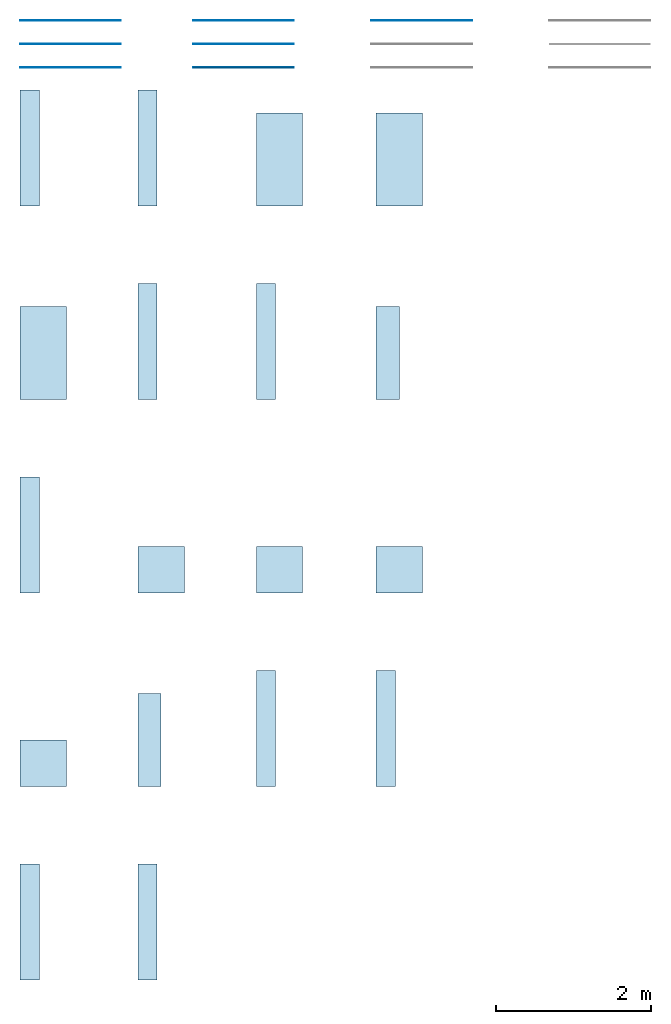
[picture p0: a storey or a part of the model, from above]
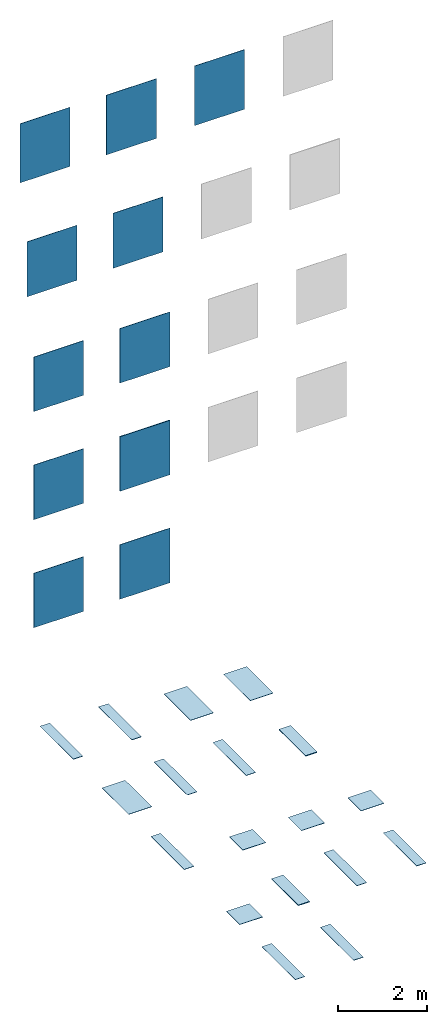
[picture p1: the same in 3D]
Properties of the parts of a building model (IFC2X3)

# File
Description: ViewDefinition [CoordinationView_V2.0], RevitIdentifiers [VersionGUID: e541cde4-21f0-433d-9453-daf3c8eb5631, NumberOfSaves: 230], CoordinateReference [CoordinateBase: Shared Coordinates, ProjectSite: Internal]
File name: Project Number
Time: 2024-11-25T10:44:30+01:00
Written by: ODA SDAI 24.3
Made in: Autodesk Revit 24.1.11.26 (ENU) - IFC 24.1.11.26

# IfcProject, Project Number
LongName: Refin-Blended; Phase: Project Status

# IfcSite, Default
RefLatitude: 51, 30, 0, 549316; RefLongitude: 0, -7, -34, -450321; RefElevation: 0 mm

# IfcBuilding
Pset_BuildingCommon - NumberOfStoreys: 1

# IfcBuildingStorey: Level:Circle Head - Project Datum (2)
Pset_AirSideSystemInformation - sets with these values: 2
Name | LongName = Name | Elevation (mm)
Level 0 | Level 0 | 0
Level 1 | Level 1 | 4000

# IfcSlab: Floor:Floor_Tiles_Refin-Eik-Almond-25x150 RJ96, Floor:Floor_Tiles_Refin-Eik-Almond-25x150 RJ96:304668
In: Level 0
Type - PredefinedType: FLOOR; Material: Eik-Almond-25x150 RJ96 9 mm, <Unnamed> 1 mm
Type - Pset_ConcreteElementGeneral - FireRating: INERT
Type - Pset_ElementShading - Color: BEIGE
Type - Pset_FireRatingProperties - SurfaceSpreadOfFlame: INERT
Type - Pset_ManufacturerOccurrence - BarCode: N/A; SerialNumber: N/A
Type - Pset_ManufacturerTypeInformation - ArticleNumber: RJ96; ModelReference: RJ96; ModelLabel: ALMOND R 25X150; Manufacturer: info@refin.it; ProductionYear: N/A
Type - Pset_PrecastConcreteElementGeneral - SerialNumber: N/A
Type - Pset_ProductRequirements - Name: Eik_Almond_25X150 R; Category: Pr_35_93_96_19:Ceramic tiles
Type - Pset_QuantityTakeOff - Reference: N/A
Type - Pset_ReinforcementBarPitchOfSlab - Description: PORCELAIN STONEWARE TILE; Reference: N/A
Type - Pset_SlabCommon - Reference: N/A; IsExternal: no; AcousticRating: N/A; FireRating: INERT; SurfaceSpreadOfFlame: INERT
Type - Pset_Warranty - WarrantyContent: N/A; Exclusions: N/A
Pset_QuantityTakeOff - sets with these values: 2
Pset_SlabCommon - LoadBearing: no; PitchAngle: 0 deg

# IfcSlab: Floor:Floor_Tiles_Refin-Eik-Ash-25x150 RJ97, Floor:Floor_Tiles_Refin-Eik-Ash-25x150 RJ97:324498
In: Level 0
Type - PredefinedType: FLOOR; Material: Eik-Ash-25x150 RJ97 9 mm, <Unnamed> 1 mm
Type - Pset_ConcreteElementGeneral - FireRating: INERT
Type - Pset_ElementShading - Color: LIGHT GREY
Type - Pset_FireRatingProperties - SurfaceSpreadOfFlame: INERT
Type - Pset_ManufacturerOccurrence - BarCode: N/A; SerialNumber: N/A
Type - Pset_ManufacturerTypeInformation - ArticleNumber: RJ97; ModelReference: RJ97; ModelLabel: ASH R 25X150; Manufacturer: info@refin.it; ProductionYear: N/A
Type - Pset_PrecastConcreteElementGeneral - SerialNumber: N/A
Type - Pset_ProductRequirements - Name: Eik_Ash_25X150 R; Category: Pr_35_93_96_19:Ceramic tiles
Type - Pset_QuantityTakeOff - Reference: N/A
Type - Pset_ReinforcementBarPitchOfSlab - Description: PORCELAIN STONEWARE TILE; Reference: N/A
Type - Pset_SlabCommon - Reference: N/A; IsExternal: no; AcousticRating: N/A; FireRating: INERT; SurfaceSpreadOfFlame: INERT
Type - Pset_Warranty - WarrantyContent: N/A; Exclusions: N/A
Pset_QuantityTakeOff - sets with these values: 2
Pset_SlabCommon - LoadBearing: no; PitchAngle: 0 deg

# IfcSlab: Floor:Floor_Tiles_Refin-Eik-Cannè-Almond-60x120 RK81, Floor:Floor_Tiles_Refin-Eik-Cannè-Almond-60x120 RK81:340715
In: Level 0
Type - PredefinedType: FLOOR; Material: Eik-Canné-Almond-60x120 RK81 9 mm, <Unnamed> 1 mm
Type - Pset_ConcreteElementGeneral - FireRating: INERT
Type - Pset_ElementShading - Color: BEIGE
Type - Pset_FireRatingProperties - SurfaceSpreadOfFlame: INERT
Type - Pset_ManufacturerOccurrence - BarCode: N/A; SerialNumber: N/A
Type - Pset_ManufacturerTypeInformation - ArticleNumber: RK81; ModelReference: RK81; ModelLabel: CANNE' ALMOND R 60X120; Manufacturer: info@refin.it; ProductionYear: N/A
Type - Pset_PrecastConcreteElementGeneral - SerialNumber: N/A
Type - Pset_ProductRequirements - Name: Eik_Cannè_Almond_60X120 R; Category: Pr_35_93_96_19:Ceramic tiles
Type - Pset_QuantityTakeOff - Reference: N/A
Type - Pset_ReinforcementBarPitchOfSlab - Description: PORCELAIN STONEWARE TILE; Reference: N/A
Type - Pset_SlabCommon - Reference: N/A; IsExternal: no; AcousticRating: N/A; FireRating: INERT; SurfaceSpreadOfFlame: INERT
Type - Pset_Warranty - WarrantyContent: N/A; Exclusions: N/A
Pset_QuantityTakeOff - sets with these values: 2
Pset_SlabCommon - LoadBearing: no; PitchAngle: 0 deg

# IfcSlab: Floor:Floor_Tiles_Refin-Eik-Cannè-Honey-60x120 RK82, Floor:Floor_Tiles_Refin-Eik-Cannè-Honey-60x120 RK82:341038
In: Level 0
Type - PredefinedType: FLOOR; Material: Eik-Canné-Honey-60x120 RK82 9 mm, <Unnamed> 1 mm
Type - Pset_ConcreteElementGeneral - FireRating: INERT
Type - Pset_ElementShading - Color: LIGHT BROWN
Type - Pset_FireRatingProperties - SurfaceSpreadOfFlame: INERT
Type - Pset_ManufacturerOccurrence - BarCode: N/A; SerialNumber: N/A
Type - Pset_ManufacturerTypeInformation - ArticleNumber: RK81; ModelReference: RK81; ModelLabel: CANNE' HONEY R 60X120; Manufacturer: info@refin.it; ProductionYear: N/A
Type - Pset_PrecastConcreteElementGeneral - SerialNumber: N/A
Type - Pset_ProductRequirements - Name: Eik_Cannè_Honey_60X120 R; Category: Pr_35_93_96_19:Ceramic tiles
Type - Pset_QuantityTakeOff - Reference: N/A
Type - Pset_ReinforcementBarPitchOfSlab - Description: PORCELAIN STONEWARE TILE; Reference: N/A
Type - Pset_SlabCommon - Reference: N/A; IsExternal: no; AcousticRating: N/A; FireRating: INERT; SurfaceSpreadOfFlame: INERT
Type - Pset_Warranty - WarrantyContent: N/A; Exclusions: N/A
Pset_QuantityTakeOff - sets with these values: 2
Pset_SlabCommon - LoadBearing: no; PitchAngle: 0 deg

# IfcSlab: Floor:Floor_Tiles_Refin-Eik-Cannè-Natural-60x120 RK83, Floor:Floor_Tiles_Refin-Eik-Cannè-Natural-60x120 RK83:341279
In: Level 0
Type - PredefinedType: FLOOR; Material: Eik-Canné-Natural-60x120 RK83 9 mm, <Unnamed> 1 mm
Type - Pset_ConcreteElementGeneral - FireRating: INERT
Type - Pset_ElementShading - Color: LIGHT BROWN
Type - Pset_FireRatingProperties - SurfaceSpreadOfFlame: INERT
Type - Pset_ManufacturerOccurrence - BarCode: N/A; SerialNumber: N/A
Type - Pset_ManufacturerTypeInformation - ArticleNumber: RK83; ModelReference: RK83; ModelLabel: CANNE' NATURAL R 60X120; Manufacturer: info@refin.it; ProductionYear: N/A
Type - Pset_PrecastConcreteElementGeneral - SerialNumber: N/A
Type - Pset_ProductRequirements - Name: Eik_Cannè_Natural_60X120 R; Category: Pr_35_93_96_19:Ceramic tiles
Type - Pset_QuantityTakeOff - Reference: N/A
Type - Pset_ReinforcementBarPitchOfSlab - Description: PORCELAIN STONEWARE TILE; Reference: N/A
Type - Pset_SlabCommon - Reference: N/A; IsExternal: no; AcousticRating: N/A; FireRating: INERT; SurfaceSpreadOfFlame: INERT
Type - Pset_Warranty - WarrantyContent: N/A; Exclusions: N/A
Pset_QuantityTakeOff - sets with these values: 2
Pset_SlabCommon - LoadBearing: no; PitchAngle: 0 deg

# IfcSlab: Floor:Floor_Tiles_Refin-Eik-Choco-25x150 RJ98, Floor:Floor_Tiles_Refin-Eik-Choco-25x150 RJ98:341467
In: Level 0
Type - PredefinedType: FLOOR; Material: Eik-Choco-25x150 RJ98 9 mm, <Unnamed> 1 mm
Type - Pset_ConcreteElementGeneral - FireRating: INERT
Type - Pset_ElementShading - Color: BROWN
Type - Pset_FireRatingProperties - SurfaceSpreadOfFlame: INERT
Type - Pset_ManufacturerOccurrence - BarCode: N/A; SerialNumber: N/A
Type - Pset_ManufacturerTypeInformation - ArticleNumber: RJ98; ModelReference: RJ98; ModelLabel: CHOCO R 25X150; Manufacturer: info@refin.it; ProductionYear: N/A
Type - Pset_PrecastConcreteElementGeneral - SerialNumber: N/A
Type - Pset_ProductRequirements - Name: Eik_Choco_25X150 R; Category: Pr_35_93_96_19:Ceramic tiles
Type - Pset_QuantityTakeOff - Reference: N/A
Type - Pset_ReinforcementBarPitchOfSlab - Description: PORCELAIN STONEWARE TILE; Reference: N/A
Type - Pset_SlabCommon - Reference: N/A; IsExternal: no; AcousticRating: N/A; FireRating: INERT; SurfaceSpreadOfFlame: INERT
Type - Pset_Warranty - WarrantyContent: N/A; Exclusions: N/A
Pset_QuantityTakeOff - sets with these values: 2
Pset_SlabCommon - LoadBearing: no; PitchAngle: 0 deg

# IfcSlab: Floor:Floor_Tiles_Refin-Eik-Coffee-25x150 RJ99, Floor:Floor_Tiles_Refin-Eik-Coffee-25x150 RJ99:341755
In: Level 0
Type - PredefinedType: FLOOR; Material: Eik-Coffee-25x150 RJ99 9 mm, <Unnamed> 1 mm
Type - Pset_ConcreteElementGeneral - FireRating: INERT
Type - Pset_ElementShading - Color: DARK BROWN
Type - Pset_FireRatingProperties - SurfaceSpreadOfFlame: INERT
Type - Pset_ManufacturerOccurrence - BarCode: N/A; SerialNumber: N/A
Type - Pset_ManufacturerTypeInformation - ArticleNumber: RJ99; ModelReference: RJ99; ModelLabel: COFFEE R 25X150; Manufacturer: info@refin.it; ProductionYear: N/A
Type - Pset_PrecastConcreteElementGeneral - SerialNumber: N/A
Type - Pset_ProductRequirements - Name: Eik_Coffee_25X150 R; Category: Pr_35_93_96_19:Ceramic tiles
Type - Pset_QuantityTakeOff - Reference: N/A
Type - Pset_ReinforcementBarPitchOfSlab - Description: PORCELAIN STONEWARE TILE; Reference: N/A
Type - Pset_SlabCommon - Reference: N/A; IsExternal: no; AcousticRating: N/A; FireRating: INERT; SurfaceSpreadOfFlame: INERT
Type - Pset_Warranty - WarrantyContent: N/A; Exclusions: N/A
Pset_QuantityTakeOff - sets with these values: 2
Pset_SlabCommon - LoadBearing: no; PitchAngle: 0 deg

# IfcSlab: Floor:Floor_Tiles_Refin-Eik-Honey-25x150 RK00, Floor:Floor_Tiles_Refin-Eik-Honey-25x150 RK00:342299
In: Level 0
Type - PredefinedType: FLOOR; Material: Eik-Honey-25x150 RK00 9 mm, <Unnamed> 1 mm
Type - Pset_ConcreteElementGeneral - FireRating: INERT
Type - Pset_ElementShading - Color: LIGHT BROWN
Type - Pset_FireRatingProperties - SurfaceSpreadOfFlame: INERT
Type - Pset_ManufacturerOccurrence - BarCode: N/A; SerialNumber: N/A
Type - Pset_ManufacturerTypeInformation - ArticleNumber: RK00; ModelReference: RK00; ModelLabel: HONEY R 25X150; Manufacturer: info@refin.it; ProductionYear: N/A
Type - Pset_PrecastConcreteElementGeneral - SerialNumber: N/A
Type - Pset_ProductRequirements - Name: Eik_Honey_25X150 R; Category: Pr_35_93_96_19:Ceramic tiles
Type - Pset_QuantityTakeOff - Reference: N/A
Type - Pset_ReinforcementBarPitchOfSlab - Description: PORCELAIN STONEWARE TILE; Reference: N/A
Type - Pset_SlabCommon - Reference: N/A; IsExternal: no; AcousticRating: N/A; FireRating: INERT; SurfaceSpreadOfFlame: INERT
Type - Pset_Warranty - WarrantyContent: N/A; Exclusions: N/A
Pset_QuantityTakeOff - sets with these values: 2
Pset_SlabCommon - LoadBearing: no; PitchAngle: 0 deg

# IfcSlab: Floor:Floor_Tiles_Refin-Eik-Honey-OUT2.0-30x120 RN20, Floor:Floor_Tiles_Refin-Eik-Honey-OUT2.0-30x120 RN20:341933
In: Level 0
Type - PredefinedType: FLOOR; Material: Eik-Honey-OUT2.0-30x120 RN20 20 mm, <Unnamed> 1 mm
Type - Pset_ConcreteElementGeneral - FireRating: INERT
Type - Pset_ElementShading - Color: LIGHT BROWN
Type - Pset_FireRatingProperties - SurfaceSpreadOfFlame: INERT
Type - Pset_ManufacturerOccurrence - BarCode: N/A; SerialNumber: N/A
Type - Pset_ManufacturerTypeInformation - ArticleNumber: RN20; ModelReference: RN20; ModelLabel: HONEY OUT2.0 R 30X120; Manufacturer: info@refin.it; ProductionYear: N/A
Type - Pset_PrecastConcreteElementGeneral - SerialNumber: N/A
Type - Pset_ProductRequirements - Name: Eik_Honey_OUT2.0_30X120 R; Category: Pr_35_93_96_19:Ceramic tiles
Type - Pset_QuantityTakeOff - Reference: N/A
Type - Pset_ReinforcementBarPitchOfSlab - Description: PORCELAIN STONEWARE TILE; Reference: N/A
Type - Pset_SlabCommon - Reference: N/A; IsExternal: no; AcousticRating: N/A; FireRating: INERT; SurfaceSpreadOfFlame: INERT
Type - Pset_Warranty - WarrantyContent: N/A; Exclusions: N/A
Pset_QuantityTakeOff - sets with these values: 2
Pset_SlabCommon - LoadBearing: no; PitchAngle: 0 deg

# IfcSlab: Floor:Floor_Tiles_Refin-Eik-Leaf-Almond-60x60 RL61, Floor:Floor_Tiles_Refin-Eik-Leaf-Almond-60x60 RL61:342545
In: Level 0
Type - PredefinedType: FLOOR; Material: Eik-Leaf-Almond-60x60 RL61 9 mm, <Unnamed> 1 mm
Type - Pset_ConcreteElementGeneral - FireRating: INERT
Type - Pset_ElementShading - Color: BEIGE
Type - Pset_FireRatingProperties - SurfaceSpreadOfFlame: INERT
Type - Pset_ManufacturerOccurrence - BarCode: N/A; SerialNumber: N/A
Type - Pset_ManufacturerTypeInformation - ArticleNumber: RL61; ModelReference: RL61; ModelLabel: LEAF ALMOND R 60X60; Manufacturer: info@refin.it; ProductionYear: N/A
Type - Pset_PrecastConcreteElementGeneral - SerialNumber: N/A
Type - Pset_ProductRequirements - Name: Eik_Leaf_Almond_60X60 R; Category: Pr_35_93_96_19:Ceramic tiles
Type - Pset_QuantityTakeOff - Reference: N/A
Type - Pset_ReinforcementBarPitchOfSlab - Description: PORCELAIN STONEWARE TILE; Reference: N/A
Type - Pset_SlabCommon - Reference: N/A; IsExternal: no; AcousticRating: N/A; FireRating: INERT; SurfaceSpreadOfFlame: INERT
Type - Pset_Warranty - WarrantyContent: N/A; Exclusions: N/A
Pset_QuantityTakeOff - sets with these values: 2
Pset_SlabCommon - LoadBearing: no; PitchAngle: 0 deg

# IfcSlab: Floor:Floor_Tiles_Refin-Eik-Leaf-Honey-60x60 RL62, Floor:Floor_Tiles_Refin-Eik-Leaf-Honey-60x60 RL62:342787
In: Level 0
Type - PredefinedType: FLOOR; Material: Eik-Leaf-Honey-60x60 RL62 9 mm, <Unnamed> 1 mm
Type - Pset_ConcreteElementGeneral - FireRating: INERT
Type - Pset_ElementShading - Color: LIGHT BROWN
Type - Pset_FireRatingProperties - SurfaceSpreadOfFlame: INERT
Type - Pset_ManufacturerOccurrence - BarCode: N/A; SerialNumber: N/A
Type - Pset_ManufacturerTypeInformation - ArticleNumber: RL62; ModelReference: RL62; ModelLabel: LEAF HONEY R 60X60; Manufacturer: info@refin.it; ProductionYear: N/A
Type - Pset_PrecastConcreteElementGeneral - SerialNumber: N/A
Type - Pset_ProductRequirements - Name: Eik_Leaf_Honey_60X60 R; Category: Pr_35_93_96_19:Ceramic tiles
Type - Pset_QuantityTakeOff - Reference: N/A
Type - Pset_ReinforcementBarPitchOfSlab - Description: PORCELAIN STONEWARE TILE; Reference: N/A
Type - Pset_SlabCommon - Reference: N/A; IsExternal: no; AcousticRating: N/A; FireRating: INERT; SurfaceSpreadOfFlame: INERT
Type - Pset_Warranty - WarrantyContent: N/A; Exclusions: N/A
Pset_QuantityTakeOff - sets with these values: 2
Pset_SlabCommon - LoadBearing: no; PitchAngle: 0 deg

# IfcSlab: Floor:Floor_Tiles_Refin-Eik-Leaf-Natural-60x60 RL63, Floor:Floor_Tiles_Refin-Eik-Leaf-Natural-60x60 RL63:342912
In: Level 0
Type - PredefinedType: FLOOR; Material: Eik-Leaf-Natural-60x60 RL63 9 mm, <Unnamed> 1 mm
Type - Pset_ConcreteElementGeneral - FireRating: INERT
Type - Pset_ElementShading - Color: LIGHT BROWN
Type - Pset_FireRatingProperties - SurfaceSpreadOfFlame: INERT
Type - Pset_ManufacturerOccurrence - BarCode: N/A; SerialNumber: N/A
Type - Pset_ManufacturerTypeInformation - ArticleNumber: RL63; ModelReference: RL63; ModelLabel: LEAF NATURAL R 60X60; Manufacturer: info@refin.it; ProductionYear: N/A
Type - Pset_PrecastConcreteElementGeneral - SerialNumber: N/A
Type - Pset_ProductRequirements - Name: Eik_Leaf_Natural_60X60 R; Category: Pr_35_93_96_19:Ceramic tiles
Type - Pset_QuantityTakeOff - Reference: N/A
Type - Pset_ReinforcementBarPitchOfSlab - Description: PORCELAIN STONEWARE TILE; Reference: N/A
Type - Pset_SlabCommon - Reference: N/A; IsExternal: no; AcousticRating: N/A; FireRating: INERT; SurfaceSpreadOfFlame: INERT
Type - Pset_Warranty - WarrantyContent: N/A; Exclusions: N/A
Pset_QuantityTakeOff - sets with these values: 2
Pset_SlabCommon - LoadBearing: no; PitchAngle: 0 deg

# IfcSlab: Floor:Floor_Tiles_Refin-Eik-Leaf-Nut-60x60 RL64, Floor:Floor_Tiles_Refin-Eik-Leaf-Nut-60x60 RL64:343152
In: Level 0
Type - PredefinedType: FLOOR; Material: Eik-Leaf-Nut-60x60 RL64 9 mm, <Unnamed> 1 mm
Type - Pset_ConcreteElementGeneral - FireRating: INERT
Type - Pset_ElementShading - Color: BROWN
Type - Pset_FireRatingProperties - SurfaceSpreadOfFlame: INERT
Type - Pset_ManufacturerOccurrence - BarCode: N/A; SerialNumber: N/A
Type - Pset_ManufacturerTypeInformation - ArticleNumber: RL64; ModelReference: RL64; ModelLabel: LEAF NUT R 60X60; Manufacturer: info@refin.it; ProductionYear: N/A
Type - Pset_PrecastConcreteElementGeneral - SerialNumber: N/A
Type - Pset_ProductRequirements - Name: Eik_Leaf_Nut_60X60 R; Category: Pr_35_93_96_19:Ceramic tiles
Type - Pset_QuantityTakeOff - Reference: N/A
Type - Pset_ReinforcementBarPitchOfSlab - Description: PORCELAIN STONEWARE TILE; Reference: N/A
Type - Pset_SlabCommon - Reference: N/A; IsExternal: no; AcousticRating: N/A; FireRating: INERT; SurfaceSpreadOfFlame: INERT
Type - Pset_Warranty - WarrantyContent: N/A; Exclusions: N/A
Pset_QuantityTakeOff - sets with these values: 2
Pset_SlabCommon - LoadBearing: no; PitchAngle: 0 deg

# IfcSlab: Floor:Floor_Tiles_Refin-Eik-Natural-25x150 RK01, Floor:Floor_Tiles_Refin-Eik-Natural-25x150 RK01:343709
In: Level 0
Type - PredefinedType: FLOOR; Material: Eik-Natural-25x150 RK01 9 mm, <Unnamed> 1 mm
Type - Pset_ConcreteElementGeneral - FireRating: INERT
Type - Pset_ElementShading - Color: LIGHT BROWN
Type - Pset_FireRatingProperties - SurfaceSpreadOfFlame: INERT
Type - Pset_ManufacturerOccurrence - BarCode: N/A; SerialNumber: N/A
Type - Pset_ManufacturerTypeInformation - ArticleNumber: RK01; ModelReference: RK01; ModelLabel: NATURAL R 25X150; Manufacturer: info@refin.it; ProductionYear: N/A
Type - Pset_PrecastConcreteElementGeneral - SerialNumber: N/A
Type - Pset_ProductRequirements - Name: Eik_Natural_25X150 R; Category: Pr_35_93_96_19:Ceramic tiles
Type - Pset_QuantityTakeOff - Reference: N/A
Type - Pset_ReinforcementBarPitchOfSlab - Description: PORCELAIN STONEWARE TILE; Reference: N/A
Type - Pset_SlabCommon - Reference: N/A; IsExternal: no; AcousticRating: N/A; FireRating: INERT; SurfaceSpreadOfFlame: INERT
Type - Pset_Warranty - WarrantyContent: N/A; Exclusions: N/A
Pset_QuantityTakeOff - sets with these values: 2
Pset_SlabCommon - LoadBearing: no; PitchAngle: 0 deg

# IfcSlab: Floor:Floor_Tiles_Refin-Eik-Natural-OUT2.0-30x120 RN21, Floor:Floor_Tiles_Refin-Eik-Natural-OUT2.0-30x120 RN21:343508
In: Level 0
Type - PredefinedType: FLOOR; Material: Eik-Natural-OUT2.0-30x120 RN21 20 mm, <Unnamed> 1 mm
Type - Pset_ConcreteElementGeneral - FireRating: INERT
Type - Pset_ElementShading - Color: LIGHT BROWN
Type - Pset_FireRatingProperties - SurfaceSpreadOfFlame: INERT
Type - Pset_ManufacturerOccurrence - BarCode: N/A; SerialNumber: N/A
Type - Pset_ManufacturerTypeInformation - ArticleNumber: RN21; ModelReference: RN21; ModelLabel: NATURAL OUT2.0 R 30X120; Manufacturer: info@refin.it; ProductionYear: N/A
Type - Pset_PrecastConcreteElementGeneral - SerialNumber: N/A
Type - Pset_ProductRequirements - Name: Eik_Natural_OUT2.0_30X120 R; Category: Pr_35_93_96_19:Ceramic tiles
Type - Pset_QuantityTakeOff - Reference: N/A
Type - Pset_ReinforcementBarPitchOfSlab - Description: PORCELAIN STONEWARE TILE; Reference: N/A
Type - Pset_SlabCommon - Reference: N/A; IsExternal: no; AcousticRating: N/A; FireRating: INERT; SurfaceSpreadOfFlame: INERT
Type - Pset_Warranty - WarrantyContent: N/A; Exclusions: N/A
Pset_QuantityTakeOff - sets with these values: 2
Pset_SlabCommon - LoadBearing: no; PitchAngle: 0 deg

# IfcSlab: Floor:Floor_Tiles_Refin-Eik-Nut-25x150 RK02, Floor:Floor_Tiles_Refin-Eik-Nut-25x150 RK02:343986
In: Level 0
Type - PredefinedType: FLOOR; Material: Eik-Nut-25x150 RK02 9 mm, <Unnamed> 1 mm
Type - Pset_ConcreteElementGeneral - FireRating: INERT
Type - Pset_ElementShading - Color: BROWN
Type - Pset_FireRatingProperties - SurfaceSpreadOfFlame: INERT
Type - Pset_ManufacturerOccurrence - BarCode: N/A; SerialNumber: N/A
Type - Pset_ManufacturerTypeInformation - ArticleNumber: RK02; ModelReference: RK02; ModelLabel: NUT R 25X150; Manufacturer: info@refin.it; ProductionYear: N/A
Type - Pset_PrecastConcreteElementGeneral - SerialNumber: N/A
Type - Pset_ProductRequirements - Name: Eik_Nut_25X150 R; Category: Pr_35_93_96_19:Ceramic tiles
Type - Pset_QuantityTakeOff - Reference: N/A
Type - Pset_ReinforcementBarPitchOfSlab - Description: PORCELAIN STONEWARE TILE; Reference: N/A
Type - Pset_SlabCommon - Reference: N/A; IsExternal: no; AcousticRating: N/A; FireRating: INERT; SurfaceSpreadOfFlame: INERT
Type - Pset_Warranty - WarrantyContent: N/A; Exclusions: N/A
Pset_QuantityTakeOff - sets with these values: 2
Pset_SlabCommon - LoadBearing: no; PitchAngle: 0 deg

# IfcSlab: Floor:Floor_Tiles_Refin-Eik-Rice-25x150 RK03, Floor:Floor_Tiles_Refin-Eik-Rice-25x150 RK03:344762
In: Level 0
Type - PredefinedType: FLOOR; Material: Eik-Rice-25x150 RK03 9 mm, <Unnamed> 1 mm
Type - Pset_ConcreteElementGeneral - FireRating: INERT
Type - Pset_ElementShading - Color: WHITE
Type - Pset_FireRatingProperties - SurfaceSpreadOfFlame: INERT
Type - Pset_ManufacturerOccurrence - BarCode: N/A; SerialNumber: N/A
Type - Pset_ManufacturerTypeInformation - ArticleNumber: RK03; ModelReference: RK03; ModelLabel: RICE R 25X150; Manufacturer: info@refin.it; ProductionYear: N/A
Type - Pset_PrecastConcreteElementGeneral - SerialNumber: N/A
Type - Pset_ProductRequirements - Name: Eik_Rice_25X150 R; Category: Pr_35_93_96_19:Ceramic tiles
Type - Pset_QuantityTakeOff - Reference: N/A
Type - Pset_ReinforcementBarPitchOfSlab - Description: PORCELAIN STONEWARE TILE; Reference: N/A
Type - Pset_SlabCommon - Reference: N/A; IsExternal: no; AcousticRating: N/A; FireRating: INERT; SurfaceSpreadOfFlame: INERT
Type - Pset_Warranty - WarrantyContent: N/A; Exclusions: N/A
Pset_QuantityTakeOff - sets with these values: 2
Pset_SlabCommon - LoadBearing: no; PitchAngle: 0 deg

# IfcSlab: Floor:Floor_Tiles_Refin-Eik-Sand-25x150 RK04, Floor:Floor_Tiles_Refin-Eik-Sand-25x150 RK04:345082
In: Level 0
Type - PredefinedType: FLOOR; Material: Eik-Sand-25x150 RK04 9 mm, <Unnamed> 1 mm
Type - Pset_ConcreteElementGeneral - FireRating: INERT
Type - Pset_ElementShading - Color: BEIGE
Type - Pset_FireRatingProperties - SurfaceSpreadOfFlame: INERT
Type - Pset_ManufacturerOccurrence - BarCode: N/A; SerialNumber: N/A
Type - Pset_ManufacturerTypeInformation - ArticleNumber: RK04; ModelReference: RK04; ModelLabel: SAND R 25X150; Manufacturer: info@refin.it; ProductionYear: N/A
Type - Pset_PrecastConcreteElementGeneral - SerialNumber: N/A
Type - Pset_ProductRequirements - Name: Eik_Sand_25X150 R; Category: Pr_35_93_96_19:Ceramic tiles
Type - Pset_QuantityTakeOff - Reference: N/A
Type - Pset_ReinforcementBarPitchOfSlab - Description: PORCELAIN STONEWARE TILE; Reference: N/A
Type - Pset_SlabCommon - Reference: N/A; IsExternal: no; AcousticRating: N/A; FireRating: INERT; SurfaceSpreadOfFlame: INERT
Type - Pset_Warranty - WarrantyContent: N/A; Exclusions: N/A
Pset_QuantityTakeOff - sets with these values: 2
Pset_SlabCommon - LoadBearing: no; PitchAngle: 0 deg

# IfcWallStandardCase: Basic Wall:Wall_Tiles_Refin-Eik-Almond-25x150 RJ96, Basic Wall:Wall_Tiles_Refin-Eik-Almond-25x150 RJ96:334895
In: Level 0
Type - PredefinedType: STANDARD; Material: <Unnamed> 1 mm, Eik-Almond-25x150 RJ96 9 mm
Type - Pset_ElementShading - Color: BEIGE
Type - Pset_FireRatingProperties - SurfaceSpreadOfFlame: INERT
Type - Pset_ManufacturerOccurrence - BarCode: N/A; SerialNumber: N/A
Type - Pset_ManufacturerTypeInformation - ArticleNumber: RJ96; ModelReference: RJ96; ModelLabel: ALMOND R 25X150; Manufacturer: info@refin.it; ProductionYear: N/A
Type - Pset_PrecastConcreteElementGeneral - SerialNumber: N/A
Type - Pset_ProductRequirements - Name: Eik_Almond_25X150 R; Category: Pr_35_93_96_19:Ceramic tiles
Type - Pset_QuantityTakeOff - Reference: N/A
Type - Pset_ReinforcementBarPitchOfWall - Description: PORCELAIN STONEWARE TILE; Reference: N/A
Type - Pset_WallCommon - Reference: N/A; IsExternal: no; AcousticRating: N/A; SurfaceSpreadOfFlame: INERT
Type - Pset_Warranty - WarrantyContent: N/A; Exclusions: N/A
Pset_QuantityTakeOff - sets with these values: 2
Pset_WallCommon - LoadBearing: no; ExtendToStructure: no

# IfcWallStandardCase: Basic Wall:Wall_Tiles_Refin-Eik-Ash-25x150 RJ97, Basic Wall:Wall_Tiles_Refin-Eik-Ash-25x150 RJ97:333696
In: Level 0
Type - PredefinedType: STANDARD; Material: <Unnamed> 1 mm, Eik-Almond-25x150 RJ96 9 mm
Type - Pset_ElementShading - Color: LIGHT GREY
Type - Pset_FireRatingProperties - SurfaceSpreadOfFlame: INERT
Type - Pset_ManufacturerOccurrence - BarCode: N/A; SerialNumber: N/A
Type - Pset_ManufacturerTypeInformation - ArticleNumber: RJ97; ModelReference: RJ97; ModelLabel: ALMOND R 25X150; Manufacturer: info@refin.it; ProductionYear: N/A
Type - Pset_PrecastConcreteElementGeneral - SerialNumber: N/A
Type - Pset_ProductRequirements - Name: Eik_Ash_25X150 R; Category: Pr_35_93_96_19:Ceramic tiles
Type - Pset_QuantityTakeOff - Reference: N/A
Type - Pset_ReinforcementBarPitchOfWall - Description: PORCELAIN STONEWARE TILE; Reference: N/A
Type - Pset_WallCommon - Reference: N/A; IsExternal: no; AcousticRating: N/A; SurfaceSpreadOfFlame: INERT
Type - Pset_Warranty - WarrantyContent: N/A; Exclusions: N/A
Pset_QuantityTakeOff - sets with these values: 2
Pset_WallCommon - LoadBearing: no; ExtendToStructure: no

# IfcWallStandardCase: Basic Wall:Wall_Tiles_Refin-Eik-Canné-Almond-60x120 RK81, Basic Wall:Wall_Tiles_Refin-Eik-Canné-Almond-60x120 RK81:334553
In: Level 0
Type - PredefinedType: STANDARD; Material: <Unnamed> 1 mm, Eik-Canné-Almond-60x120 RK81 9 mm
Type - Pset_ElementShading - Color: BEIGE
Type - Pset_FireRatingProperties - SurfaceSpreadOfFlame: INERT
Type - Pset_ManufacturerOccurrence - BarCode: N/A; SerialNumber: N/A
Type - Pset_ManufacturerTypeInformation - ArticleNumber: RK81; ModelReference: RK81; ModelLabel: CANNE' ALMOND R 60X120; Manufacturer: info@refin.it; ProductionYear: N/A
Type - Pset_PrecastConcreteElementGeneral - SerialNumber: N/A
Type - Pset_ProductRequirements - Name: Eik_Canné_Almond_60X120 R; Category: Pr_35_93_96_19:Ceramic tiles
Type - Pset_QuantityTakeOff - Reference: N/A
Type - Pset_ReinforcementBarPitchOfWall - Description: PORCELAIN STONEWARE TILE; Reference: N/A
Type - Pset_WallCommon - Reference: N/A; IsExternal: no; AcousticRating: N/A; SurfaceSpreadOfFlame: INERT
Type - Pset_Warranty - WarrantyContent: N/A; Exclusions: N/A
Pset_QuantityTakeOff - sets with these values: 2
Pset_WallCommon - LoadBearing: no; ExtendToStructure: no

# IfcWallStandardCase: Basic Wall:Wall_Tiles_Refin-Eik-Canné-Honey-60x120 RK82, Basic Wall:Wall_Tiles_Refin-Eik-Canné-Honey-60x120 RK82:341158
In: Level 0
Type - PredefinedType: STANDARD; Material: <Unnamed> 1 mm, Eik-Canné-Honey-60x120 RK82 9 mm
Type - Pset_ElementShading - Color: LIGHT BROWN
Type - Pset_FireRatingProperties - SurfaceSpreadOfFlame: INERT
Type - Pset_ManufacturerOccurrence - BarCode: N/A; SerialNumber: N/A
Type - Pset_ManufacturerTypeInformation - ArticleNumber: RK82; ModelReference: RK82; ModelLabel: CANNE' HONEY R 60X120; Manufacturer: info@refin.it; ProductionYear: N/A
Type - Pset_PrecastConcreteElementGeneral - SerialNumber: N/A
Type - Pset_ProductRequirements - Name: Eik_Canné_Honey_60X120 R; Category: Pr_35_93_96_19:Ceramic tiles
Type - Pset_QuantityTakeOff - Reference: N/A
Type - Pset_ReinforcementBarPitchOfWall - Description: PORCELAIN STONEWARE TILE; Reference: N/A
Type - Pset_WallCommon - Reference: N/A; IsExternal: no; AcousticRating: N/A; SurfaceSpreadOfFlame: INERT
Type - Pset_Warranty - WarrantyContent: N/A; Exclusions: N/A
Pset_QuantityTakeOff - sets with these values: 2
Pset_WallCommon - LoadBearing: no; ExtendToStructure: no

# IfcWallStandardCase: Basic Wall:Wall_Tiles_Refin-Eik-Canné-Natural-60x120 RK83, Basic Wall:Wall_Tiles_Refin-Eik-Canné-Natural-60x120 RK83:335038
In: Level 0
Type - PredefinedType: STANDARD; Material: <Unnamed> 1 mm, Eik-Canné-Natural-60x120 RK83 9 mm
Type - Pset_ElementShading - Color: LIGHT BROWN
Type - Pset_FireRatingProperties - SurfaceSpreadOfFlame: INERT
Type - Pset_ManufacturerOccurrence - BarCode: N/A; SerialNumber: N/A
Type - Pset_ManufacturerTypeInformation - ArticleNumber: RK83; ModelReference: RK83; ModelLabel: CANNE' NATURAL R 60X120; Manufacturer: info@refin.it; ProductionYear: N/A
Type - Pset_PrecastConcreteElementGeneral - SerialNumber: N/A
Type - Pset_ProductRequirements - Name: Eik_Canné_Natural_60X120 R; Category: Pr_35_93_96_19:Ceramic tiles
Type - Pset_QuantityTakeOff - Reference: N/A
Type - Pset_ReinforcementBarPitchOfWall - Description: PORCELAIN STONEWARE TILE; Reference: N/A
Type - Pset_WallCommon - Reference: N/A; IsExternal: no; AcousticRating: N/A; SurfaceSpreadOfFlame: INERT
Type - Pset_Warranty - WarrantyContent: N/A; Exclusions: N/A
Pset_QuantityTakeOff - sets with these values: 2
Pset_WallCommon - LoadBearing: no; ExtendToStructure: no

# IfcWallStandardCase: Basic Wall:Wall_Tiles_Refin-Eik-Choco-25x150 RJ98, Basic Wall:Wall_Tiles_Refin-Eik-Choco-25x150 RJ98:335490
In: Level 0
Type - PredefinedType: STANDARD; Material: <Unnamed> 1 mm, Eik-Choco-25x150 RJ98 9 mm
Type - Pset_ElementShading - Color: BROWN
Type - Pset_FireRatingProperties - SurfaceSpreadOfFlame: INERT
Type - Pset_ManufacturerOccurrence - BarCode: N/A; SerialNumber: N/A
Type - Pset_ManufacturerTypeInformation - ArticleNumber: RJ98; ModelReference: RJ98; ModelLabel: CHOCO R 25X150; Manufacturer: info@refin.it; ProductionYear: N/A
Type - Pset_PrecastConcreteElementGeneral - SerialNumber: N/A
Type - Pset_ProductRequirements - Name: Eik_Choco_25X150 R; Category: Pr_35_93_96_19:Ceramic tiles
Type - Pset_QuantityTakeOff - Reference: N/A
Type - Pset_ReinforcementBarPitchOfWall - Description: PORCELAIN STONEWARE TILE; Reference: N/A
Type - Pset_WallCommon - Reference: N/A; IsExternal: no; AcousticRating: N/A; SurfaceSpreadOfFlame: INERT
Type - Pset_Warranty - WarrantyContent: N/A; Exclusions: N/A
Pset_QuantityTakeOff - sets with these values: 2
Pset_WallCommon - LoadBearing: no; ExtendToStructure: no

# IfcWallStandardCase: Basic Wall:Wall_Tiles_Refin-Eik-Coffee-25x150 RJ99, Basic Wall:Wall_Tiles_Refin-Eik-Coffee-25x150 RJ99:335882
In: Level 0
Type - PredefinedType: STANDARD; Material: <Unnamed> 1 mm, Eik-Coffee-25x150 RJ99 9 mm
Type - Pset_ElementShading - Color: DARK BROWN
Type - Pset_FireRatingProperties - SurfaceSpreadOfFlame: INERT
Type - Pset_ManufacturerOccurrence - BarCode: N/A; SerialNumber: N/A
Type - Pset_ManufacturerTypeInformation - ArticleNumber: RJ99; ModelReference: RJ99; ModelLabel: COFFEE R 25X150; Manufacturer: info@refin.it; ProductionYear: N/A
Type - Pset_PrecastConcreteElementGeneral - SerialNumber: N/A
Type - Pset_ProductRequirements - Name: Eik_Coffee_25X150 R; Category: Pr_35_93_96_19:Ceramic tiles
Type - Pset_QuantityTakeOff - Reference: N/A
Type - Pset_ReinforcementBarPitchOfWall - Description: PORCELAIN STONEWARE TILE; Reference: N/A
Type - Pset_WallCommon - Reference: N/A; IsExternal: no; AcousticRating: N/A; SurfaceSpreadOfFlame: INERT
Type - Pset_Warranty - WarrantyContent: N/A; Exclusions: N/A
Pset_QuantityTakeOff - sets with these values: 2
Pset_WallCommon - LoadBearing: no; ExtendToStructure: no

# IfcWallStandardCase: Basic Wall:Wall_Tiles_Refin-Eik-Honey-25x150 RK00, Basic Wall:Wall_Tiles_Refin-Eik-Honey-25x150 RK00:336183
In: Level 0
Type - PredefinedType: STANDARD; Material: <Unnamed> 1 mm, Eik-Honey-25x150 RK00 9 mm
Type - Pset_ElementShading - Color: LIGHT BROWN
Type - Pset_FireRatingProperties - SurfaceSpreadOfFlame: INERT
Type - Pset_ManufacturerOccurrence - BarCode: N/A; SerialNumber: N/A
Type - Pset_ManufacturerTypeInformation - ArticleNumber: RK00; ModelReference: RK00; ModelLabel: HONEY R 25X150; Manufacturer: info@refin.it; ProductionYear: N/A
Type - Pset_PrecastConcreteElementGeneral - SerialNumber: N/A
Type - Pset_ProductRequirements - Name: Eik_Honey_25X150 R; Category: Pr_35_93_96_19:Ceramic tiles
Type - Pset_QuantityTakeOff - Reference: N/A
Type - Pset_ReinforcementBarPitchOfWall - Description: PORCELAIN STONEWARE TILE; Reference: N/A
Type - Pset_WallCommon - Reference: N/A; IsExternal: no; AcousticRating: N/A; SurfaceSpreadOfFlame: INERT
Type - Pset_Warranty - WarrantyContent: N/A; Exclusions: N/A
Pset_QuantityTakeOff - sets with these values: 2
Pset_WallCommon - LoadBearing: no; ExtendToStructure: no

# IfcWallStandardCase: Basic Wall:Wall_Tiles_Refin-Eik-Honey-OUT2.0-30x120 RN20, Basic Wall:Wall_Tiles_Refin-Eik-Honey-OUT2.0-30x120 RN20:340784
In: Level 0
Type - PredefinedType: STANDARD; Material: <Unnamed> 1 mm, Eik-Honey-OUT2.0-30x120 RN20 20 mm
Type - Pset_ElementShading - Color: LIGHT BROWN
Type - Pset_FireRatingProperties - SurfaceSpreadOfFlame: INERT
Type - Pset_ManufacturerOccurrence - BarCode: N/A; SerialNumber: N/A
Type - Pset_ManufacturerTypeInformation - ArticleNumber: RN20; ModelReference: RN20; ModelLabel: HONEY OUT2.0 R 30X120; Manufacturer: info@refin.it; ProductionYear: N/A
Type - Pset_PrecastConcreteElementGeneral - SerialNumber: N/A
Type - Pset_ProductRequirements - Name: Eik_Honey_OUT2.0_30X120 R; Category: Pr_35_93_96_19:Ceramic tiles
Type - Pset_QuantityTakeOff - Reference: N/A
Type - Pset_ReinforcementBarPitchOfWall - Description: PORCELAIN STONEWARE TILE; Reference: N/A
Type - Pset_WallCommon - Reference: N/A; IsExternal: no; AcousticRating: N/A; SurfaceSpreadOfFlame: INERT
Type - Pset_Warranty - WarrantyContent: N/A; Exclusions: N/A
Pset_QuantityTakeOff - sets with these values: 2
Pset_WallCommon - LoadBearing: no; ExtendToStructure: no

# IfcWallStandardCase: Basic Wall:Wall_Tiles_Refin-Eik-Leaf-Almond-60x60 RL61, Basic Wall:Wall_Tiles_Refin-Eik-Leaf-Almond-60x60 RL61:342594
In: Level 0
Type - PredefinedType: STANDARD; Material: <Unnamed> 1 mm, Eik-Leaf-Almond-60x60 RL61 9 mm
Type - Pset_ElementShading - Color: BEIGE
Type - Pset_FireRatingProperties - SurfaceSpreadOfFlame: INERT
Type - Pset_ManufacturerOccurrence - BarCode: N/A; SerialNumber: N/A
Type - Pset_ManufacturerTypeInformation - ArticleNumber: RL61; ModelReference: RL61; ModelLabel: LEAF ALMOND R 60X60; Manufacturer: info@refin.it; ProductionYear: N/A
Type - Pset_PrecastConcreteElementGeneral - SerialNumber: N/A
Type - Pset_ProductRequirements - Name: Eik_Leaf_Almond_60X60 R; Category: Pr_35_93_96_19:Ceramic tiles
Type - Pset_QuantityTakeOff - Reference: N/A
Type - Pset_ReinforcementBarPitchOfWall - Description: PORCELAIN STONEWARE TILE; Reference: N/A
Type - Pset_WallCommon - Reference: N/A; IsExternal: no; AcousticRating: N/A; SurfaceSpreadOfFlame: INERT
Type - Pset_Warranty - WarrantyContent: N/A; Exclusions: N/A
Pset_QuantityTakeOff - sets with these values: 2
Pset_WallCommon - LoadBearing: no; ExtendToStructure: no

# IfcWallStandardCase: Basic Wall:Wall_Tiles_Refin-Eik-Leaf-Honey-60x60 RL62, Basic Wall:Wall_Tiles_Refin-Eik-Leaf-Honey-60x60 RL62:342842
In: Level 0
Type - PredefinedType: STANDARD; Material: <Unnamed> 1 mm, Eik-Leaf-Honey-60x60 RL62 9 mm
Type - Pset_ElementShading - Color: LIGHT BROWN
Type - Pset_FireRatingProperties - SurfaceSpreadOfFlame: INERT
Type - Pset_ManufacturerOccurrence - BarCode: N/A; SerialNumber: N/A
Type - Pset_ManufacturerTypeInformation - ArticleNumber: RL62; ModelReference: RL62; ModelLabel: LEAF HONEY R 60X60; Manufacturer: info@refin.it; ProductionYear: N/A
Type - Pset_PrecastConcreteElementGeneral - SerialNumber: N/A
Type - Pset_ProductRequirements - Name: Eik_Leaf_Honey_60X60 R; Category: Pr_35_93_96_19:Ceramic tiles
Type - Pset_QuantityTakeOff - Reference: N/A
Type - Pset_ReinforcementBarPitchOfWall - Description: PORCELAIN STONEWARE TILE; Reference: N/A
Type - Pset_WallCommon - Reference: N/A; IsExternal: no; AcousticRating: N/A; SurfaceSpreadOfFlame: INERT
Type - Pset_Warranty - WarrantyContent: N/A; Exclusions: N/A
Pset_QuantityTakeOff - sets with these values: 2
Pset_WallCommon - LoadBearing: no; ExtendToStructure: no

# IfcWallStandardCase: Basic Wall:Wall_Tiles_Refin-Eik-Leaf-Natural-60x60 RL63, Basic Wall:Wall_Tiles_Refin-Eik-Leaf-Natural-60x60 RL63:342942
In: Level 0
Type - PredefinedType: STANDARD; Material: <Unnamed> 1 mm, Eik-Leaf-Natural-60x60 RL63 9 mm
Type - Pset_ElementShading - Color: LIGHT BROWN
Type - Pset_FireRatingProperties - SurfaceSpreadOfFlame: INERT
Type - Pset_ManufacturerOccurrence - BarCode: N/A; SerialNumber: N/A
Type - Pset_ManufacturerTypeInformation - ArticleNumber: RL63; ModelReference: RL63; ModelLabel: LEAF NATURAL R 60X60; Manufacturer: info@refin.it; ProductionYear: N/A
Type - Pset_PrecastConcreteElementGeneral - SerialNumber: N/A
Type - Pset_ProductRequirements - Name: Eik_Leaf_Natural_60X60 R; Category: Pr_35_93_96_19:Ceramic tiles
Type - Pset_QuantityTakeOff - Reference: N/A
Type - Pset_ReinforcementBarPitchOfWall - Description: PORCELAIN STONEWARE TILE; Reference: N/A
Type - Pset_WallCommon - Reference: N/A; IsExternal: no; AcousticRating: N/A; SurfaceSpreadOfFlame: INERT
Type - Pset_Warranty - WarrantyContent: N/A; Exclusions: N/A
Pset_QuantityTakeOff - sets with these values: 2
Pset_WallCommon - LoadBearing: no; ExtendToStructure: no

# IfcWallStandardCase: Basic Wall:Wall_Tiles_Refin-Eik-Leaf-Nut-60x60 RL64, Basic Wall:Wall_Tiles_Refin-Eik-Leaf-Nut-60x60 RL64:343330
In: Level 0
Type - PredefinedType: STANDARD; Material: <Unnamed> 1 mm, Eik-Leaf-Nut-60x60 RL64 9 mm
Type - Pset_ElementShading - Color: BROWN
Type - Pset_FireRatingProperties - SurfaceSpreadOfFlame: INERT
Type - Pset_ManufacturerOccurrence - BarCode: N/A; SerialNumber: N/A
Type - Pset_ManufacturerTypeInformation - ArticleNumber: RL64; ModelReference: RL64; ModelLabel: LEAF NUT R 60X60; Manufacturer: info@refin.it; ProductionYear: N/A
Type - Pset_PrecastConcreteElementGeneral - SerialNumber: N/A
Type - Pset_ProductRequirements - Name: Eik_Leaf_Nut_60X60 R; Category: Pr_35_93_96_19:Ceramic tiles
Type - Pset_QuantityTakeOff - Reference: N/A
Type - Pset_ReinforcementBarPitchOfWall - Description: PORCELAIN STONEWARE TILE; Reference: N/A
Type - Pset_WallCommon - Reference: N/A; IsExternal: no; AcousticRating: N/A; SurfaceSpreadOfFlame: INERT
Type - Pset_Warranty - WarrantyContent: N/A; Exclusions: N/A
Pset_QuantityTakeOff - sets with these values: 2
Pset_WallCommon - LoadBearing: no; ExtendToStructure: no

# IfcWallStandardCase: Basic Wall:Wall_Tiles_Refin-Eik-Natural-25x150 RK01, Basic Wall:Wall_Tiles_Refin-Eik-Natural-25x150 RK01:343836
In: Level 0
Type - PredefinedType: STANDARD; Material: <Unnamed> 1 mm, Eik-Natural-25x150 RK01 9 mm
Type - Pset_ElementShading - Color: LIGHT BROWN
Type - Pset_FireRatingProperties - SurfaceSpreadOfFlame: INERT
Type - Pset_ManufacturerOccurrence - BarCode: N/A; SerialNumber: N/A
Type - Pset_ManufacturerTypeInformation - ArticleNumber: RK01; ModelReference: RK01; ModelLabel: NATURAL R 25X150; Manufacturer: info@refin.it; ProductionYear: N/A
Type - Pset_PrecastConcreteElementGeneral - SerialNumber: N/A
Type - Pset_ProductRequirements - Name: Eik_Natural_25X150 R; Category: Pr_35_93_96_19:Ceramic tiles
Type - Pset_QuantityTakeOff - Reference: N/A
Type - Pset_ReinforcementBarPitchOfWall - Description: PORCELAIN STONEWARE TILE; Reference: N/A
Type - Pset_WallCommon - Reference: N/A; IsExternal: no; AcousticRating: N/A; SurfaceSpreadOfFlame: INERT
Type - Pset_Warranty - WarrantyContent: N/A; Exclusions: N/A
Pset_QuantityTakeOff - sets with these values: 2
Pset_WallCommon - LoadBearing: no; ExtendToStructure: no

# IfcWallStandardCase: Basic Wall:Wall_Tiles_Refin-Eik-Natural-OUT2.0-30x120 RN21, Basic Wall:Wall_Tiles_Refin-Eik-Natural-OUT2.0-30x120 RN21:343548
In: Level 0
Type - PredefinedType: STANDARD; Material: <Unnamed> 1 mm, Eik-Natural-OUT2.0-30x120 RN21 20 mm
Type - Pset_ElementShading - Color: LIGHT BROWN
Type - Pset_FireRatingProperties - SurfaceSpreadOfFlame: INERT
Type - Pset_ManufacturerOccurrence - BarCode: N/A; SerialNumber: N/A
Type - Pset_ManufacturerTypeInformation - ArticleNumber: RN21; ModelReference: RN21; ModelLabel: NATURAL OUT2.0 R 30X120; Manufacturer: info@refin.it; ProductionYear: N/A
Type - Pset_PrecastConcreteElementGeneral - SerialNumber: N/A
Type - Pset_ProductRequirements - Name: Eik_Natural_OUT2.0_30X120 R; Category: Pr_35_93_96_19:Ceramic tiles
Type - Pset_QuantityTakeOff - Reference: N/A
Type - Pset_ReinforcementBarPitchOfWall - Description: PORCELAIN STONEWARE TILE; Reference: N/A
Type - Pset_WallCommon - Reference: N/A; IsExternal: no; AcousticRating: N/A; SurfaceSpreadOfFlame: INERT
Type - Pset_Warranty - WarrantyContent: N/A; Exclusions: N/A
Pset_QuantityTakeOff - sets with these values: 2
Pset_WallCommon - LoadBearing: no; ExtendToStructure: no

# IfcWallStandardCase: Basic Wall:Wall_Tiles_Refin-Eik-Nut-25x150 RK02, Basic Wall:Wall_Tiles_Refin-Eik-Nut-25x150 RK02:344019
In: Level 0
Type - PredefinedType: STANDARD; Material: <Unnamed> 1 mm, Eik-Nut-25x150 RK02 9 mm
Type - Pset_ElementShading - Color: BROWN
Type - Pset_FireRatingProperties - SurfaceSpreadOfFlame: INERT
Type - Pset_ManufacturerOccurrence - BarCode: N/A; SerialNumber: N/A
Type - Pset_ManufacturerTypeInformation - ArticleNumber: RK02; ModelReference: RK02; ModelLabel: NUT R 25X150; Manufacturer: info@refin.it; ProductionYear: N/A
Type - Pset_PrecastConcreteElementGeneral - SerialNumber: N/A
Type - Pset_ProductRequirements - Name: Eik_Nut_25X150 R; Category: Pr_35_93_96_19:Ceramic tiles
Type - Pset_QuantityTakeOff - Reference: N/A
Type - Pset_ReinforcementBarPitchOfWall - Description: PORCELAIN STONEWARE TILE; Reference: N/A
Type - Pset_WallCommon - Reference: N/A; IsExternal: no; AcousticRating: N/A; SurfaceSpreadOfFlame: INERT
Type - Pset_Warranty - WarrantyContent: N/A; Exclusions: N/A
Pset_QuantityTakeOff - sets with these values: 2
Pset_WallCommon - LoadBearing: no; ExtendToStructure: no

# IfcWallStandardCase: Basic Wall:Wall_Tiles_Refin-Eik-Rice-25x150 RK03, Basic Wall:Wall_Tiles_Refin-Eik-Rice-25x150 RK03:344949
In: Level 0
Type - PredefinedType: STANDARD; Material: <Unnamed> 1 mm, Eik-Rice-25x150 RK03 9 mm
Type - Pset_ElementShading - Color: WHITE
Type - Pset_FireRatingProperties - SurfaceSpreadOfFlame: INERT
Type - Pset_ManufacturerOccurrence - BarCode: N/A; SerialNumber: N/A
Type - Pset_ManufacturerTypeInformation - ArticleNumber: RK03; ModelReference: RK03; ModelLabel: RICE R 25X150; Manufacturer: info@refin.it; ProductionYear: N/A
Type - Pset_PrecastConcreteElementGeneral - SerialNumber: N/A
Type - Pset_ProductRequirements - Name: Eik_Rice_25X150 R; Category: Pr_35_93_96_19:Ceramic tiles
Type - Pset_QuantityTakeOff - Reference: N/A
Type - Pset_ReinforcementBarPitchOfWall - Description: PORCELAIN STONEWARE TILE; Reference: N/A
Type - Pset_WallCommon - Reference: N/A; IsExternal: no; AcousticRating: N/A; SurfaceSpreadOfFlame: INERT
Type - Pset_Warranty - WarrantyContent: N/A; Exclusions: N/A
Pset_QuantityTakeOff - sets with these values: 2
Pset_WallCommon - LoadBearing: no; ExtendToStructure: no

# IfcWallStandardCase: Basic Wall:Wall_Tiles_Refin-Eik-Sand-25x150 RK04, Basic Wall:Wall_Tiles_Refin-Eik-Sand-25x150 RK04:345111
In: Level 0
Type - PredefinedType: STANDARD; Material: <Unnamed> 1 mm, Eik-Sand-25x150 RK04 9 mm
Type - Pset_ElementShading - Color: BEIGE
Type - Pset_FireRatingProperties - SurfaceSpreadOfFlame: INERT
Type - Pset_ManufacturerOccurrence - BarCode: N/A; SerialNumber: N/A
Type - Pset_ManufacturerTypeInformation - ArticleNumber: RK04; ModelReference: RK04; ModelLabel: SAND R 25X150; Manufacturer: info@refin.it; ProductionYear: N/A
Type - Pset_PrecastConcreteElementGeneral - SerialNumber: N/A
Type - Pset_ProductRequirements - Name: Eik_Sand_25X150 R; Category: Pr_35_93_96_19:Ceramic tiles
Type - Pset_QuantityTakeOff - Reference: N/A
Type - Pset_ReinforcementBarPitchOfWall - Description: PORCELAIN STONEWARE TILE; Reference: N/A
Type - Pset_WallCommon - Reference: N/A; IsExternal: no; AcousticRating: N/A; SurfaceSpreadOfFlame: INERT
Type - Pset_Warranty - WarrantyContent: N/A; Exclusions: N/A
Pset_QuantityTakeOff - sets with these values: 2
Pset_WallCommon - LoadBearing: no; ExtendToStructure: no
